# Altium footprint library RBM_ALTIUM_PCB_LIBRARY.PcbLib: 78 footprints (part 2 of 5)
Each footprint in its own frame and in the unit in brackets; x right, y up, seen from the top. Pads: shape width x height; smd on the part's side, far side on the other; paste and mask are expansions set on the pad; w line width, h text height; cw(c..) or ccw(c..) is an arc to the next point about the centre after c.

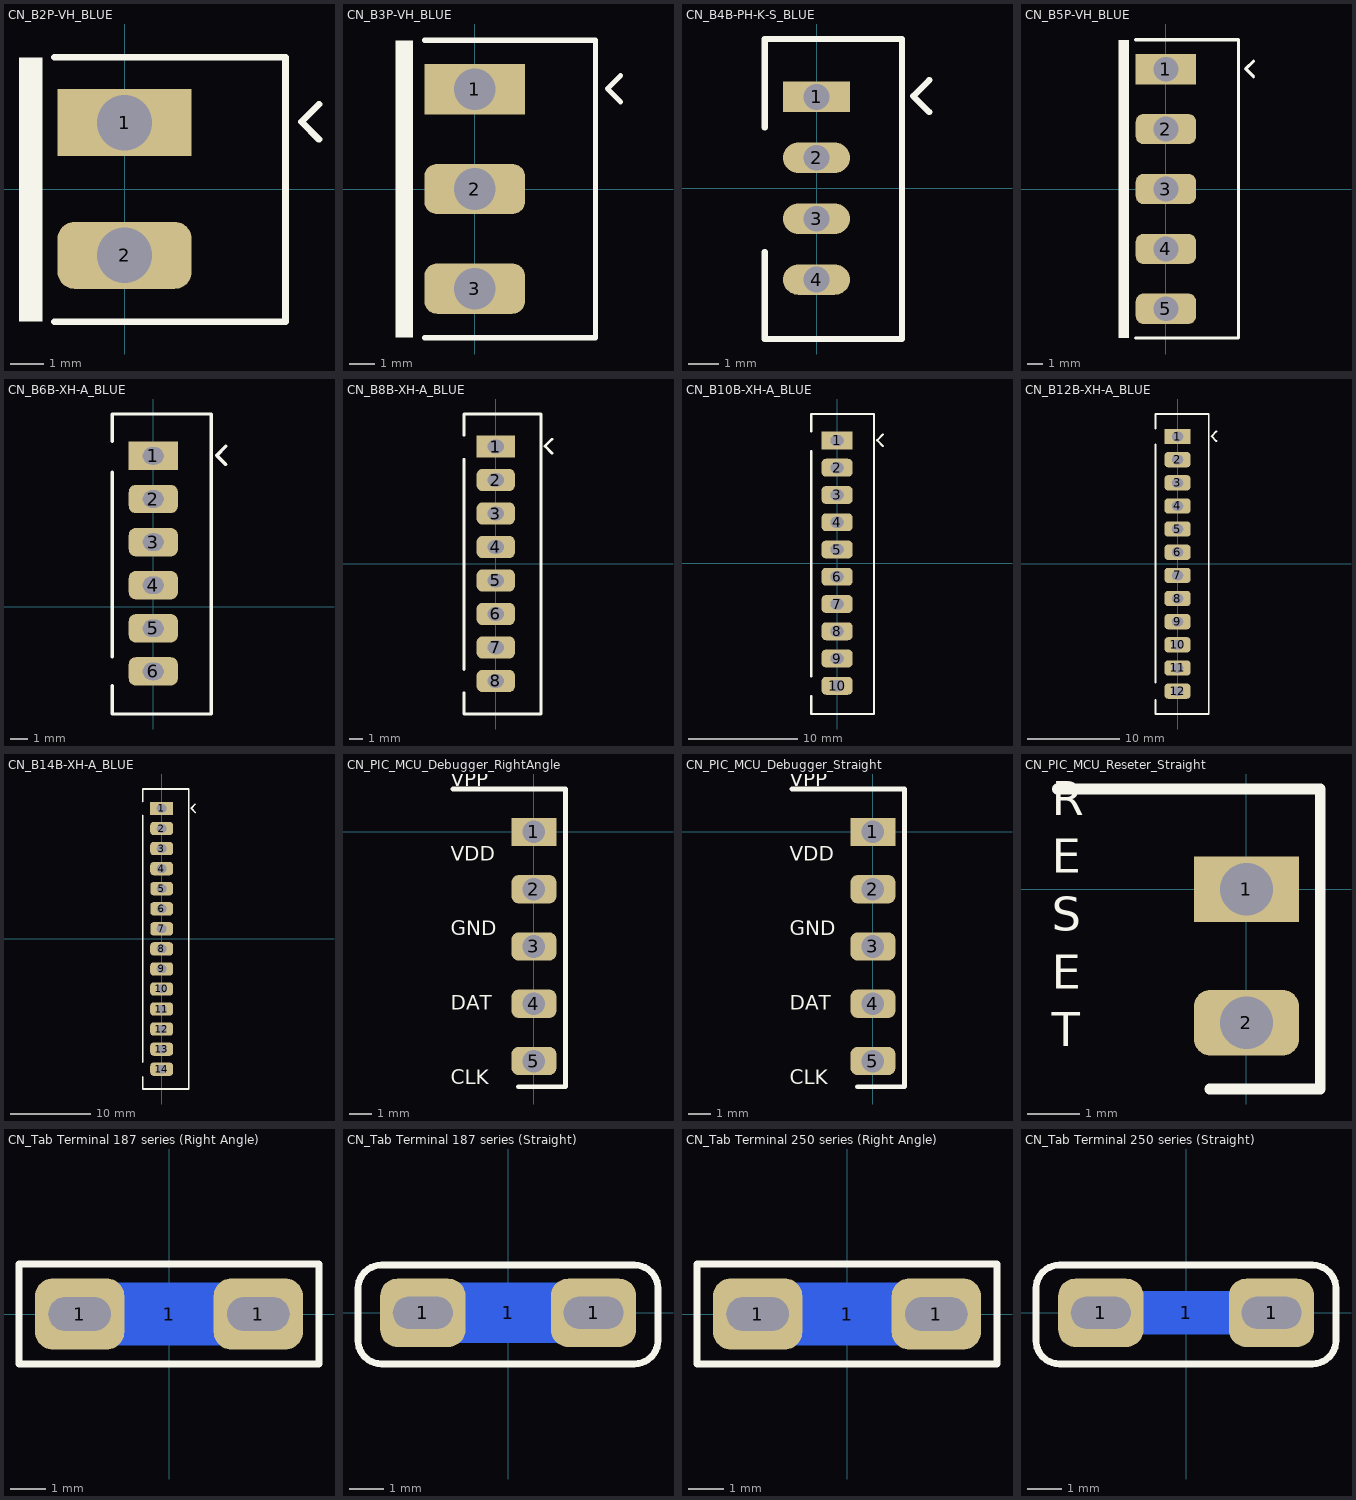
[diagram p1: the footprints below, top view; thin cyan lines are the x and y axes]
## CN_B2P-VH_BLUE [mm] "3.96mm Pitch"
pads (2):
  rect 4x2 hole 1.65: 1(0,1.98)
  rrect50% 4x2 hole 1.65: 2(0,-1.98)
Top Overlay:
  rectangle: -3.15,-3.96 -2.45,3.93
  lines w0.2: -2.1,-3.96 4.8,-3.96 4.8,3.93 -2.1,3.93 ; 5.8,1.48 5.275,2.005 5.8,2.53
3D body "B2P-VH.STEP": height 10.9, standoff -3.7, extent -3.75,-3.96 4.75,3.9

## CN_B3P-VH_BLUE [mm] "3.96mm Pitch"
pads (3):
  rect 4x2 hole 1.65: 1(0,3.96)
  rrect50% 4x2 hole 1.65: 2(0,0) 3(0,-3.96)
Top Overlay:
  rectangle: -3.15,-5.91 -2.45,5.91
  lines w0.2: -2,-5.91 4.8,-5.91 4.8,5.91 -2,5.91 ; 5.8,3.46 5.275,3.985 5.8,4.51
3D body "B3P-VH.STEP": height 10.9, standoff -3.7, extent -3.7,-5.91 4.8,5.91

## CN_B4B-PH-K-S_BLUE [mm] "Top Entry Header 2mm pitch 1X4pin  180° long"
pads (4):
  rect 2.2x1 hole 0.85: 1(0,3)
  oval 2.2x1 hole 0.85: 2(0,1) 3(0,-1) 4(0,-3)
Top Overlay:
  lines w0.2: -1.7,-2.1 -1.7,-4.95 2.8,-4.95 2.8,4.9 -1.7,4.9 -1.7,2 ; 3.7,2.5 3.175,3.025 3.7,3.55
3D body "B4B-PH-K-S.STEP": height 6, standoff -3.4, extent -1.7,-5 2.8,4.9

## CN_B5P-VH_BLUE [mm] "3.96mm Pitch"
pads (5):
  rect 4x2 hole 1.65: 1(0,7.92)
  rrect50% 4x2 hole 1.65: 2(0,3.96) 3(0,0) 4(0,-3.96) 5(0,-7.92)
Top Overlay:
  rectangle: -3.15,-9.85 -2.45,9.87
  lines w0.2: -2,-9.85 4.8,-9.85 4.8,9.87 -2,9.87 ; 5.8,7.42 5.275,7.945 5.8,8.47
3D body "B5P-VH.STEP": height 10.9, standoff -3.7, extent -3.65,-9.85 4.85,9.89

## CN_B6B-XH-A_BLUE [mm] "2.5mm Pitch, 8pins, Top-Entry, XH Connector"
pads (6):
  rect 2.85x1.65 hole 1.2 slot 1 at 90 deg: 1(0,8.75)
  rrect50% 2.85x1.65 hole 1.2 slot 1 at 90 deg: 2(0,6.25) 3(0,3.75) 4(0,1.25) 5(0,-1.25) 6(0,-3.75)
Top Overlay:
  lines w0.2: -2.375,-6.22 3.375,-6.22 3.375,11.18 -2.375,11.18 -2.375,9.6 ; -2.375,-6.15 -2.375,-4.57 ; -2.375,-2.9 -2.375,7.8 ; 4.2,8.25 3.675,8.775 4.2,9.3
3D body "B6B-XH-A.STEP": height 7, standoff -3.4, extent -2.375,-6.22 3.375,11.18

## CN_B8B-XH-A_BLUE [mm] "2.5mm Pitch, 8pins, Top-Entry, XH Connector"
pads (8):
  rect 2.85x1.65 hole 1.2 slot 1 at 90 deg: 1(0,8.75)
  rrect50% 2.85x1.65 hole 1.2 slot 1 at 90 deg: 2(0,6.25) 3(0,3.75) 4(0,1.25) 5(0,-1.25) 6(0,-3.75) 7(0,-6.25) 8(0,-8.75)
Top Overlay:
  lines w0.2: -2.375,-9.64 -2.375,-11.22 3.375,-11.22 3.375,11.18 -2.375,11.18 -2.375,9.6 ; -2.375,-7.9 -2.375,7.8 ; 4.2,8.25 3.675,8.775 4.2,9.3
3D body "B8B-XH-A.STEP": height 7, standoff -3.4, extent -2.375,-11.22 3.375,11.18

## CN_B10B-XH-A_BLUE [mm] "2.5mmPitch, TopEntry, BlueColor, XH Connector"
pads (10):
  rect 2.85x1.65 hole 1.2 slot 1 at 90 deg: 1(0,11.25)
  rrect50% 2.85x1.65 hole 1.2 slot 1 at 90 deg: 2(0,8.75) 3(0,6.25) 4(0,3.75) 5(0,1.25) 6(0,-1.25) 7(0,-3.75) 8(0,-6.25) 9(0,-8.75) 10(0,-11.25)
Top Overlay:
  lines w0.2: -2.375,-12.2 -2.375,-13.84 3.375,-13.84 3.375,13.68 -2.375,13.68 -2.375,12.1 ; -2.375,-10.4 -2.375,10.3 ; 4.2,10.75 3.675,11.275 4.2,11.8
3D body "B10B-XH-A.STEP": height 7, standoff -3.4, extent -2.375,-13.72 3.375,13.68

## CN_B12B-XH-A_BLUE [mm] "2.5mmPitch, TopEntry, BlueColor, XH Connector"
pads (12):
  rect 2.85x1.65 hole 1.2 slot 1 at 90 deg: 1(0,13.75)
  rrect50% 2.85x1.65 hole 1.2 slot 1 at 90 deg: 2(0,11.25) 3(0,8.75) 4(0,6.25) 5(0,3.75) 6(0,1.25) 7(0,-1.25) 8(0,-3.75) 9(0,-6.25) 10(0,-8.75) 11(0,-11.25) 12(0,-13.75)
Top Overlay:
  lines w0.2: -2.375,-14.7 -2.375,-16.22 3.375,-16.22 3.375,16.18 -2.375,16.18 -2.375,14.6 ; -2.375,-12.8 -2.375,12.9 ; 4.2,13.25 3.675,13.775 4.2,14.3
3D body "B12B-XH-A.STEP": height 7, standoff -3.4, extent -2.375,-16.22 3.375,16.18

## CN_B14B-XH-A_BLUE [mm] "2.5mmPitch, TopEntry, BlueColor, XH Connector"
pads (14):
  rect 2.85x1.65 hole 1.2 slot 1 at 90 deg: 1(0,16.25)
  rrect50% 2.85x1.65 hole 1.2 slot 1 at 90 deg: 2(0,13.75) 3(0,11.25) 4(0,8.75) 5(0,6.25) 6(0,3.75) 7(0,1.25) 8(0,-1.25) 9(0,-3.75) 10(0,-6.25) 11(0,-8.75) 12(0,-11.25) 13(0,-13.75) 14(0,-16.25)
Top Overlay:
  lines w0.2: -2.375,-17.2 -2.375,-18.72 3.375,-18.72 3.375,18.68 -2.375,18.68 -2.375,17.1 ; -2.375,-15.4 -2.375,15.4 ; 4.2,15.75 3.675,16.275 4.2,16.8
3D body "B14B-XH-A.STEP": height 7, standoff -3.4, extent -2.375,-18.72 3.375,18.68

## CN_PIC_MCU_Debugger_RightAngle [mm] "2.54mmPitch, 5pins, StraightType, Male Connector"
pads (5):
  rect 2x1.25 hole 1: 1(0,0)
  rrect50% 2x1.25 hole 1: 2(0,-2.54) 3(0,-5.08) 4(0,-7.62) 5(0,-10.16)
Top Overlay:
  lines w0.203: -3.6,1.905 1.4,1.905 1.4,-11.3 -0.7,-11.3
  text "VPP /  /  / VDD /  /  / GND /  /  / DAT /  /  / CLK" at -3.7,-11.4 h1.1
Bottom Overlay:
  lines w0.203: -3.6,1.9 1.4,1.9 1.4,-11.305 -0.7,-11.305
  text "VPP /  /  / VDD /  /  / GND /  /  / DAT /  /  / CLK" at -1.3,-11.4 h1.1
3D body "5-Way 2.54mm Right Angle Male Header.STEP": height 2.51, standoff -3, extent -0.365,-11.4 9.765,1.3

## CN_PIC_MCU_Debugger_Straight [mm] "2.54mmPitch, 5pins, StraightType, Male Connector"
pads (5):
  rect 2x1.25 hole 1: 1(0,0)
  rrect50% 2x1.25 hole 1: 2(0,-2.54) 3(0,-5.08) 4(0,-7.62) 5(0,-10.16)
Top Overlay:
  lines w0.203: -3.6,1.905 1.4,1.905 1.4,-11.3 -0.7,-11.3
  text "VPP /  /  / VDD /  /  / GND /  /  / DAT /  /  / CLK" at -3.7,-11.4 h1.1
Bottom Overlay:
  lines w0.203: -3.6,1.9 1.4,1.9 1.4,-11.305 -0.7,-11.305
  text "VPP /  /  / VDD /  /  / GND /  /  / DAT /  /  / CLK" at -1.3,-11.4 h1.1
3D body "5Pins 2.54mm Male Header.STEP": height 8.54, standoff -3, extent -1.245,-11.43 1.245,1.27

## CN_PIC_MCU_Reseter_Straight [mm] "2.54mmPitch, 2pins, StraightType, Male Connector"
pads (2):
  rect 2x1.25 hole 1: 1(0,0)
  rrect50% 2x1.25 hole 1: 2(0,-2.54)
Top Overlay:
  lines w0.203: -3.6,1.905 1.4,1.905 1.4,-3.8 -0.7,-3.8
  text "R / E / S / E / T" at -3.7,-3.2 h1.1
Bottom Overlay:
  lines w0.203: -3.6,1.9 1.4,1.9 1.4,-3.8 -0.7,-3.8
  text "R / E / S / E / T" at -1.3,-3.2 h1.1
3D body "User Library-Header_Male_2Pin.STEP": height 8.54, standoff -3, extent -1.245,-3.81 1.245,1.27

## CN_Tab Terminal 187 series (Right Angle) [mm]
pads (3):
  rrect50% 2.5x2 hole 0.95 slot 1.75 at 0 deg: 1(-2.5,0) 1(2.5,0)
  rect 2.85x1.75 smd far side: 1(0,0)
Top Overlay:
  lines w0.2: -4.2,-1.397 -4.2,1.397 4.2,1.397 4.2,-1.397 -4.2,-1.397
3D body "4.8mm PCB Tab Terminal (Right Angle).stp": height 9.3, standoff -3.7, extent -3.3,-0.4 9.5,0.4

## CN_Tab Terminal 187 series (Straight) [mm]
pads (3):
  rrect50% 2.5x2 hole 0.95 slot 1.75 at 0 deg: 1(-2.5,0) 1(2.5,0)
  rect 2.85x1.75 smd far side: 1(0,0)
Top Overlay:
  lines w0.2: -4.4,-0.81 ccw(c-3.712,-0.81) -3.712,-1.498 3.7,-1.497 ccw(c3.7,-0.81) 4.388,-0.81 ; -4.4,-0.8 -4.4,0.712 ; -4.4,0.71 cw(c-3.712,0.71) -3.712,1.398 ; -3.712,1.397 3.7,1.397 ; 3.7,1.398 cw(c3.7,0.71) 4.388,0.71 ; 4.388,-0.812 4.388,0.7
3D body "4.8mm PCB Tab Terminal (Straight).stp": height 9, standoff -3.45, extent -3.962,-1.3 3.962,1.494

## CN_Tab Terminal 250 series (Right Angle) [mm]
pads (3):
  rrect50% 2.5x2 hole 0.95 slot 1.75 at 0 deg: 1(-2.5,0) 1(2.5,0)
  rect 2.85x1.75 smd far side: 1(0,0)
Top Overlay:
  lines w0.2: -4.2,-1.397 4.2,-1.397 4.2,1.397 -4.2,1.397 -4.2,-1.397
3D body "6.3mm PCB Tab Terminal (Right Angle).STEP": height 9.1, standoff -2.9, extent -4,-0.4 12.2,0.4

## CN_Tab Terminal 250 series (Straight) [mm]
pads (3):
  rrect50% 2.5x2 hole 0.95 slot 1.75 at 0 deg: 1(-2.5,0) 1(2.5,0)
  rect 2.85x1.25 smd far side: 1(0,0)
Top Overlay:
  lines w0.2: -4.4,-0.81 ccw(c-3.712,-0.81) -3.712,-1.498 3.7,-1.497 ccw(c3.7,-0.81) 4.388,-0.81 ; -4.4,-0.8 -4.4,0.712 ; -4.4,0.71 cw(c-3.712,0.71) -3.712,1.398 ; -3.712,1.397 3.7,1.397 ; 3.7,1.398 cw(c3.7,0.71) 4.388,0.71 ; 4.388,-0.812 4.388,0.7
3D body "6.3mm PCB Tab Terminal (Straight).stp": height 10.2, standoff -3.8, extent -4,-0.4 4,0.4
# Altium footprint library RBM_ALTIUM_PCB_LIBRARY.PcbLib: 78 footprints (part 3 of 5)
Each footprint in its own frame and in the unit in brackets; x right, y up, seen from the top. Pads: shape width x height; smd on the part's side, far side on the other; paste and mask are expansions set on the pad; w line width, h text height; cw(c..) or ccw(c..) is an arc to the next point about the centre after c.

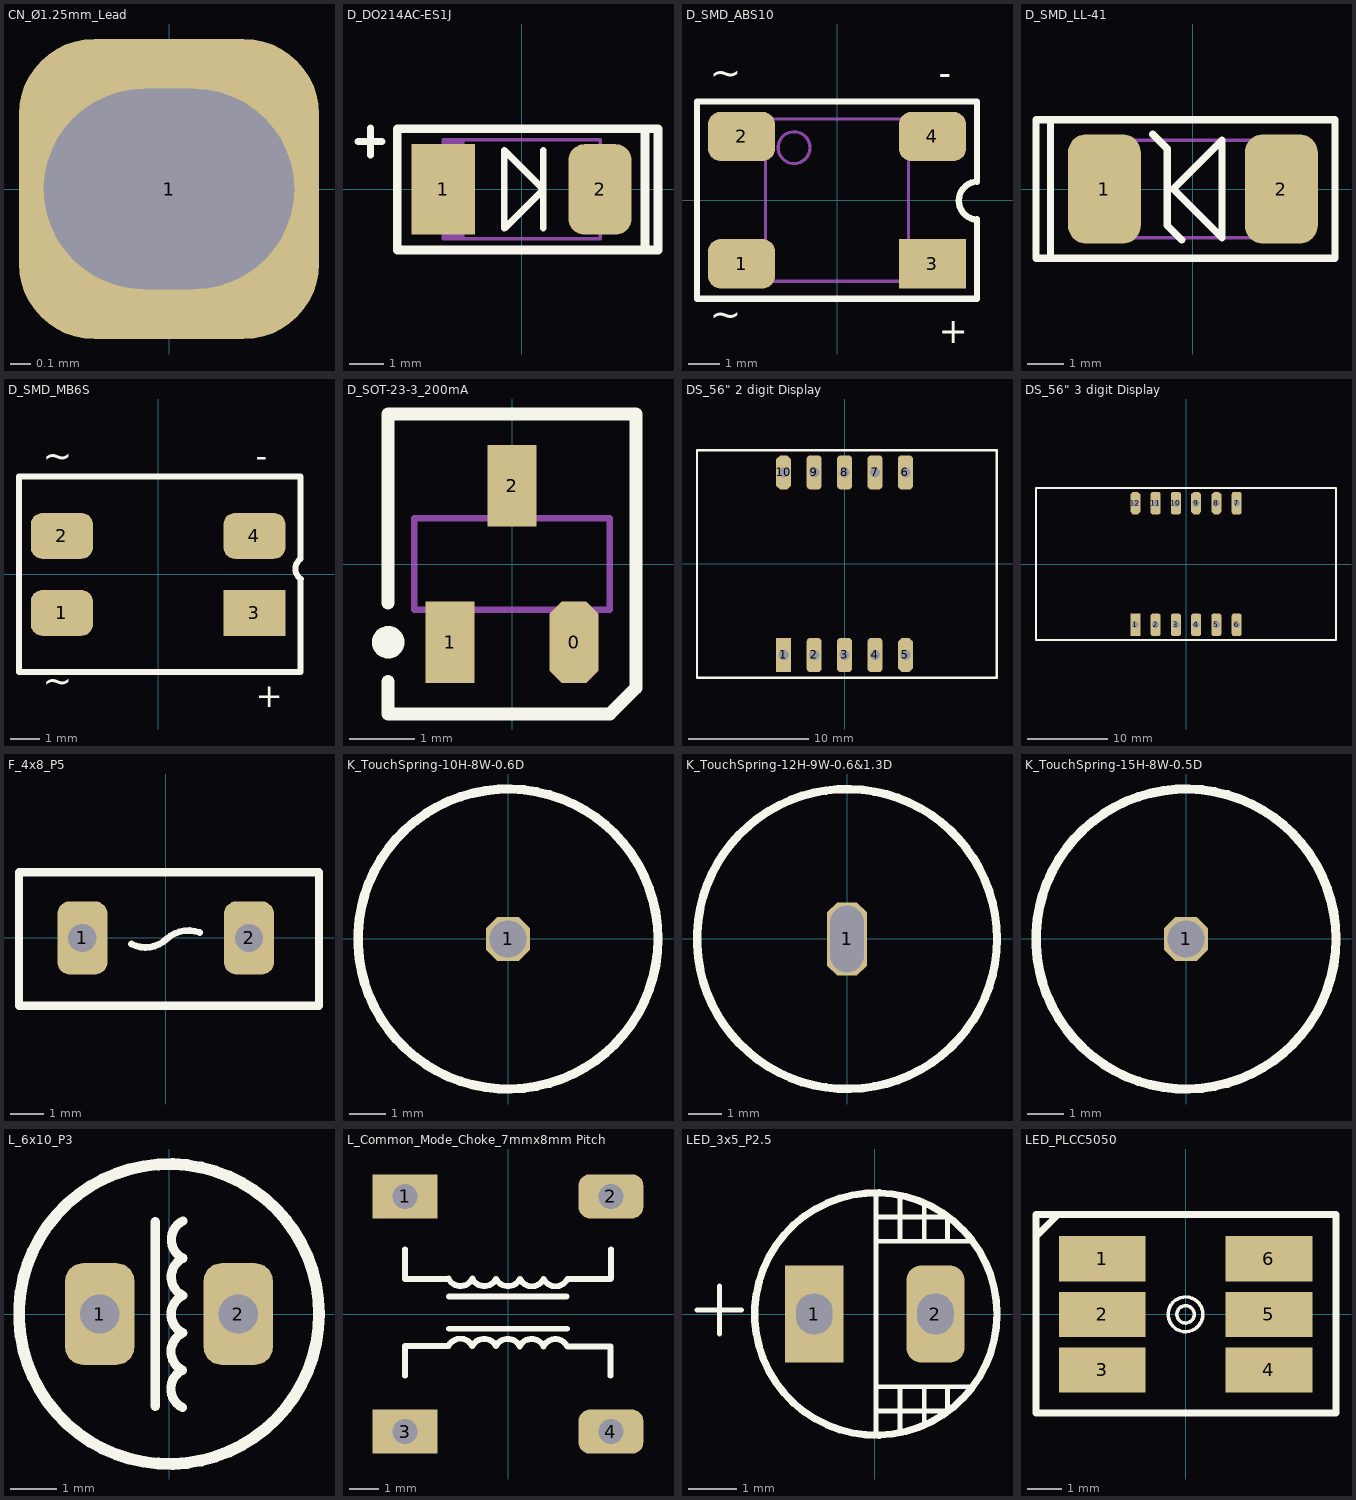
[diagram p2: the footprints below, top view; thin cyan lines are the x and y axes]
## CN_Ø1.25mm_Lead [mm] "Lead Wire"
pads (1):
  rrect50% 1.5x1.5 / inner rrect50% 1.5x1.5 / far side rrect50% 2.5x1.5 hole 1.25 slot 1 at 90 deg: 1(0,0)

## D_DO214AC-ES1J [mm] "Molded Diode, 2-Leads, Body 4.29x2.69mm, IPC Medium Density"
height 2.44
pads (2):
  rect 1.85x2.65 smd: 1(-2.3,0)
  rrect50% 1.85x2.65 smd: 2(2.3,0)
Top Overlay:
  lines w0.2: -4.8,1.4 -4.1,1.4 ; -4.435,1 -4.435,1.8 ; 0.635,-1.143 0.635,1.143 ; -0.508,-1.143 0.635,0 -0.508,1.143 -0.508,-1.143
  lines w0.254: 3.619,-1.778 3.619,1.778 ; -3.65,-1.778 4,-1.778 4,1.778 -3.65,1.778 -3.65,-1.778
Mechanical 13:
  rectangle: -2.3,-1.45 -1.681,1.45
  lines w0.1: -2.3,-1.45 2.3,-1.45 2.3,1.45 -2.3,1.45 -2.3,-1.45
3D body "DIOM4327X24N.step": height 2.44, standoff 0, extent -2.52,-1.45 2.52,1.45

## D_SMD_ABS10 [mm]
pads (4):
  rrect50% 2.1x1.55 smd: 1(-3,-2) 2(-3,2) 4(3,2)
  rect 2.1x1.55 smd: 3(3,-2)
Top Overlay:
  lines w0.2: 4.299,-0.603 cw(c4.427,-0.017) 4.306,0.57 ; 4.4,-0.603 4.4,-3.1 -4.4,-3.1 -4.4,3.1 4.4,3.1 4.4,0.57
  text "~" at -4,-4.3 h1.5
  text "-" at 3.2,4.2 h0.8
  text "+" at 3.2,-3.8 h0.8
  text "~" at -4,3.3 h1.5
Mechanical 13:
  circle w0.1: c-1.35,1.65 r0.5
  lines w0.1: -2.25,-2.55 -2.25,2.55 2.25,2.55 2.25,-2.55 -2.25,-2.55
3D body "TSOP400P650X160-4N.step": height 1.6, standoff 0, extent -3.25,-2.55 3.25,2.55

## D_SMD_LL-41 [mm]
height 2.67
pads (2):
  rrect50% 2x3 smd: 1(-2.425,0) 2(2.425,0)
Top Overlay:
  lines w0.2: -3.9,-1.8 -3.9,1.8 ; -1.1,1.5 -0.7,1.1 -0.7,-1 -0.3,-1.4 ; -4.3,-1.9 3.9,-1.9 3.9,1.9 -4.3,1.9 -4.3,-1.9 ; -0.535,0 0.8,1.335 0.8,-1.335 -0.535,0
Mechanical 13:
  lines w0.1: -2.75,-1.335 -2.75,1.335 2.75,1.335 2.75,-1.335 -2.75,-1.335
3D body "ZD.step": height 2.46, standoff 0.01, extent -2.575,-1.227 2.575,1.228

## D_SMD_MB6S [mm]
pads (4):
  rrect50% 2.1x1.55 smd: 1(-3.25,-1.3) 2(-3.25,1.3) 4(3.25,1.3)
  rect 2.1x1.55 smd: 3(3.25,-1.3)
Top Overlay:
  lines w0.2: 4.8,-0.153 4.8,-3.3 -4.7,-3.3 -4.7,3.3 4.8,3.3 4.8,0.523 ; 4.813,0.523 ccw(c5.028,0.186) 4.816,-0.153
  text "~" at -3.9,-4.3 h1.5
  text "-" at 3.3,4.2 h0.8
  text "+" at 3.3,-3.8 h0.8
  text "~" at -3.9,3.3 h1.5
3D body "User Library-moste3k.STEP": height 1.45, standoff -0.08, extent -3.447,-2.417 3.453,2.577

## D_SOT-23-3_200mA [mm] "Diodes - General Purpose 100V 200mA 1.25V @ 200mA SOT-23(SOT-23-3) RoHS"
height 1.15
pads (3):
  oct 0.75x1.25 smd: 0(0.95,-1.2)
  rect 0.75x1.25 smd: 1(-0.95,-1.2) 2(0,1.2)
Top Overlay:
  circle w0.25: c-1.9,-1.2 r0.125
  lines w0.2: -1.9,-1.8 -1.9,-2.3 1.5,-2.3 1.9,-1.9 1.9,2.3 -1.9,2.3 -1.9,-0.6
Mechanical 13:
  lines w0.1: -1.5,-0.7 1.5,-0.7 1.5,0.7 -1.5,0.7 -1.5,-0.7
3D body "SOT95P245X115-3N.step": height 1.15, standoff 0, extent -1.5,-1.3 1.5,1.3

## DS_56" 2 digit Display [mm]
pads (10):
  rect 1.25x2.85 hole 0.85: 1(-5.08,-7.62)
  rrect50% 1.25x2.85 hole 0.85: 2(-2.54,-7.62) 3(0,-7.62) 4(2.54,-7.62) 6(5.08,7.62) 7(2.54,7.62) 8(0,7.62) 9(-2.54,7.62)
  oct 1.25x2.85 hole 0.85: 5(5.08,-7.62) 10(-5.08,7.62)
Top Overlay:
  lines w0.2: -12.319,-9.525 -12.319,9.475 12.7,9.475 12.7,-9.525 ; -12.28,-9.525 12.72,-9.525
Bottom Overlay:
  text "D2" at 5.8,-5 h1
  text "D1" at -4.4,4.1 h1
  text "a" at 2.9,4.167 h1
  text "b" at 5.38,4.167 h1
  text "f" at 0.301,4.167 h1
  text "g" at -2.24,4.3 h1
  text "c" at 2.742,-4.833 h1
  text "e" at 0.201,-4.833 h1
  text "dp" at -1.738,-4.9 h1
  text "d" at -4.878,-4.833 h1
3D body: height 3, standoff -3, extent -5.338,7.361 -4.82,7.88
3D body: height 3, standoff -3, extent -2.798,7.361 -2.28,7.88
3D body: height 3, standoff -3, extent -0.258,7.361 0.26,7.88
3D body: height 3, standoff -3, extent 2.282,7.361 2.8,7.88
3D body: height 3, standoff -3, extent 4.822,7.361 5.34,7.88
3D body: height 3, standoff -3, extent -5.338,-7.879 -4.82,-7.36
3D body: height 3, standoff -3, extent 4.822,-7.879 5.34,-7.36
3D body: height 3, standoff -3, extent 2.282,-7.879 2.8,-7.36
3D body: height 3, standoff -3, extent -0.258,-7.879 0.26,-7.36
3D body: height 3, standoff -3, extent -2.798,-7.879 -2.28,-7.36
3D body: height 7, standoff 1, extent -12.319,-9.525 12.7,9.398
3D body: height 7, standoff 1, extent -12.3,-9.313 12.719,9.61
3D body: height 8.1, standoff -5.5, extent -16.11,10.118 -16.11,10.118

## DS_56" 3 digit Display [mm]
pads (12):
  rect 1.25x2.85 hole 0.85: 1(-6.35,-7.62)
  rrect50% 1.25x2.85 hole 0.85: 2(-3.81,-7.62) 3(-1.27,-7.62) 4(1.27,-7.62) 5(3.81,-7.62) 6(6.35,-7.62) 7(6.35,7.62) 10(-1.27,7.62) 11(-3.81,7.62)
  oct 1.25x2.85 hole 0.85: 8(3.81,7.62) 9(1.27,7.62) 12(-6.35,7.62)
Top Overlay:
  lines w0.2: -18.796,-9.525 -18.796,9.525 18.796,9.525 18.796,-9.525 -18.796,-9.525
Bottom Overlay:
  text "D1" at -5.67,4.2 h1
  text "D2" at 2.13,4.2 h1
  text "D3" at 4.64,4.2 h1
  text "d" at -3.5,-4.8 h1
  text "dp" at -0.5,-4.7 h1
  text "e" at -6.1,-4.767 h1
  text "c" at 1.6,-4.7 h1
  text "g" at 4.1,-4.567 h1
  text "f" at -1.07,4.3 h1
  text "b" at 6.73,4.2 h1
  text "a" at -3.37,4.3 h1
3D body "User Library-5631_w_o_color_jam.step": height 8.1, standoff -5.5, extent -18.796,-9.525 18.804,9.475

## F_4x8_P5 [mm]
pads (2):
  rrect50% 1.5x2.2 hole 0.85: 1(-2.5,0) 2(2.5,0)
Top Overlay:
  lines w0.2: -1.028,-0.184 ccw(c-0.609,0.633) 0.034,-0.022 ; 0.001,-0.057 cw(c0.685,-0.753) 1.023,0.162
  lines w0.254: -4.402,-2.032 4.598,-2.032 4.598,1.968 -4.402,1.968 -4.402,-2.032
3D body: height 7, standoff 0.68, extent -4.505,-1.968 4.512,1.968
3D body: height 1.5, standoff -2, extent -2.797,-0.299 -2.199,0.3
3D body: height 1.5, standoff -2, extent 2.203,-0.299 2.801,0.3

## K_TouchSpring-10H-8W-0.6D [mm]
pads (1):
  oct 1.2x1.2 / inner oct 1x1 / far side oct 2.5x2.5 hole 1: 1(0,0)
Top Overlay:
  circle w0.254: c0,0 r4.09
3D body: height 3, standoff -3, extent 0,0 0,0
3D body: height 10, standoff 0, extent -4,-3.997 4,3.997
3D body: height 3, standoff -3, extent -0.258,-0.259 0.26,0.26

## K_TouchSpring-12H-9W-0.6&1.3D [mm]
pads (1):
  oct 1.2x2.2 / inner oct 1x1 / far side oct 3x3 hole 2 slot 1 at 0 deg: 1(0,0)
Top Overlay:
  circle w0.254: c0,0 r4.5
3D body: height 12, standoff 0, extent -4.5,-4.5 4.5,4.5
3D body: height 3, standoff -3, extent 0,0 0,0
3D body: height 5, standoff -3, extent -0.3,-0.7 0.3,0.7

## K_TouchSpring-15H-8W-0.5D [mm]
pads (1):
  oct 1.2x1.2 / inner oct 1x1 / far side oct 2.5x2.5 hole 1: 1(0,0)
Top Overlay:
  circle w0.254: c0,0 r4.09
3D body: height 3, standoff -3, extent -0.258,-0.259 0.26,0.26
3D body: height 15, standoff 0, extent -4,-3.997 4,3.997
3D body: height 3, standoff -3, extent 0,0 0,0

## L_6x10_P3 [mm]
pads (2):
  rrect50% 1.5x2.2 hole 0.85: 1(-1.5,0) 2(1.5,0)
Top Overlay:
  circle w0.254: c0,0 r3.25
  lines w0.2: -0.3,-2 -0.3,2 ; 0.293,-2.025 cw(c0.489,-1.622) 0.295,-1.217 cw(c0.492,-0.813) 0.298,-0.408 cw(c0.494,-0.005) 0.3,0.4 cw(c0.497,0.804) 0.302,1.208 cw(c0.499,1.612) 0.305,2.017
3D body: height 2, standoff -1, extent 1.202,-0.299 1.8,0.3
3D body: height 2, standoff -1, extent -1.799,-0.299 -1.201,0.299
3D body: height 13, standoff 10, extent -3.242,-3.316 3.258,3.177
3D body: height 3.25, standoff 0.25, extent -3.242,-3.316 3.258,3.177
3D body: height 11.5, standoff 0.5, extent -2.993,-3.07 3.006,2.93

## L_Common_Mode_Choke_7mmx8mm Pitch [mm] "1~22mH, 1000~200mA"
pads (4):
  rect 2.2x1.5 hole 0.85: 1(-3.5,4) 3(-3.5,-4)
  rrect50% 2.2x1.5 hole 0.85: 2(3.5,4) 4(3.5,-4)
Top Overlay:
  lines w0.2: -3.5,-2.1 -3.5,-1.093 -2.025,-1.093 cw(c-1.622,-1.289) -1.217,-1.095 cw(c-0.813,-1.292) -0.408,-1.098 cw(c-0.005,-1.294) 0.4,-1.1 cw(c0.804,-1.297) 1.208,-1.102 cw(c1.612,-1.299) 2.017,-1.105 3.488,-1.105 3.488,-2.1 ; -3.5,2.2 -3.5,1.193 -2.034,1.193 -2.022,1.205 ccw(c-1.617,1.399) -1.213,1.202 ccw(c-0.808,1.397) -0.405,1.2 ccw(c0,1.394) 0.404,1.198 ccw(c0.808,1.392) 1.212,1.195 ccw(c1.617,1.389) 2.02,1.193 3.488,1.193 3.5,1.205 3.5,2.2 ; -2.005,0.6 1.995,0.6 ; -2,-0.5 2,-0.5

## LED_3x5_P2.5 [mm]
pads (2):
  rect 1.2x2 hole 0.85 slot 0.75 at 0 deg: 1(-1.25,0)
  rrect50% 1.2x2 hole 0.85 slot 0.75 at 0 deg: 2(1.25,0)
Top Overlay:
  circle w0.15: c0.02,0 r2.5
  lines w0.1: -3.67,0.083 -2.754,0.083 ; -3.203,-0.417 -3.203,0.583 ; 0.02,-2.5 0.02,2.5 ; 0.02,-2 1.5,-2 1.5,-1.5 ; 0.02,-1.5 2.014,-1.5 ; 0.02,1.5 2.014,1.5 ; 0.02,2 1.5,2 1.5,1.5 ; 0.52,-2.4 0.52,-1.5 ; 0.52,1.5 0.52,2.4 ; 1.02,-2.3 1.02,-1.5 ; 1.02,1.5 1.02,2.3
3D body "LED_3x5_P2.5.STEP": height 7.38, standoff -1.17, extent -1.974,-1.498 2.014,1.994

## LED_PLCC5050 [mm] "EDISON RGB .2W"
pads (6):
  rect 2.5x1.3 smd: 1(-2.4,1.6) 2(-2.4,0) 3(-2.4,-1.6) 4(2.4,-1.6) 5(2.4,0) 6(2.4,1.6)
Top Overlay:
  circle w0.1: c0,0 r0.5
  circle w0.1: c0,0 r0.25
  lines w0.2: -4.305,2.235 -3.67,2.87 ; -4.305,-2.845 4.331,-2.845 4.331,2.87 -4.305,2.87 -4.305,-2.845
3D body "User Library-APA102C.step": height 1.51, standoff -0.04, extent -2.75,-2.5 2.75,2.5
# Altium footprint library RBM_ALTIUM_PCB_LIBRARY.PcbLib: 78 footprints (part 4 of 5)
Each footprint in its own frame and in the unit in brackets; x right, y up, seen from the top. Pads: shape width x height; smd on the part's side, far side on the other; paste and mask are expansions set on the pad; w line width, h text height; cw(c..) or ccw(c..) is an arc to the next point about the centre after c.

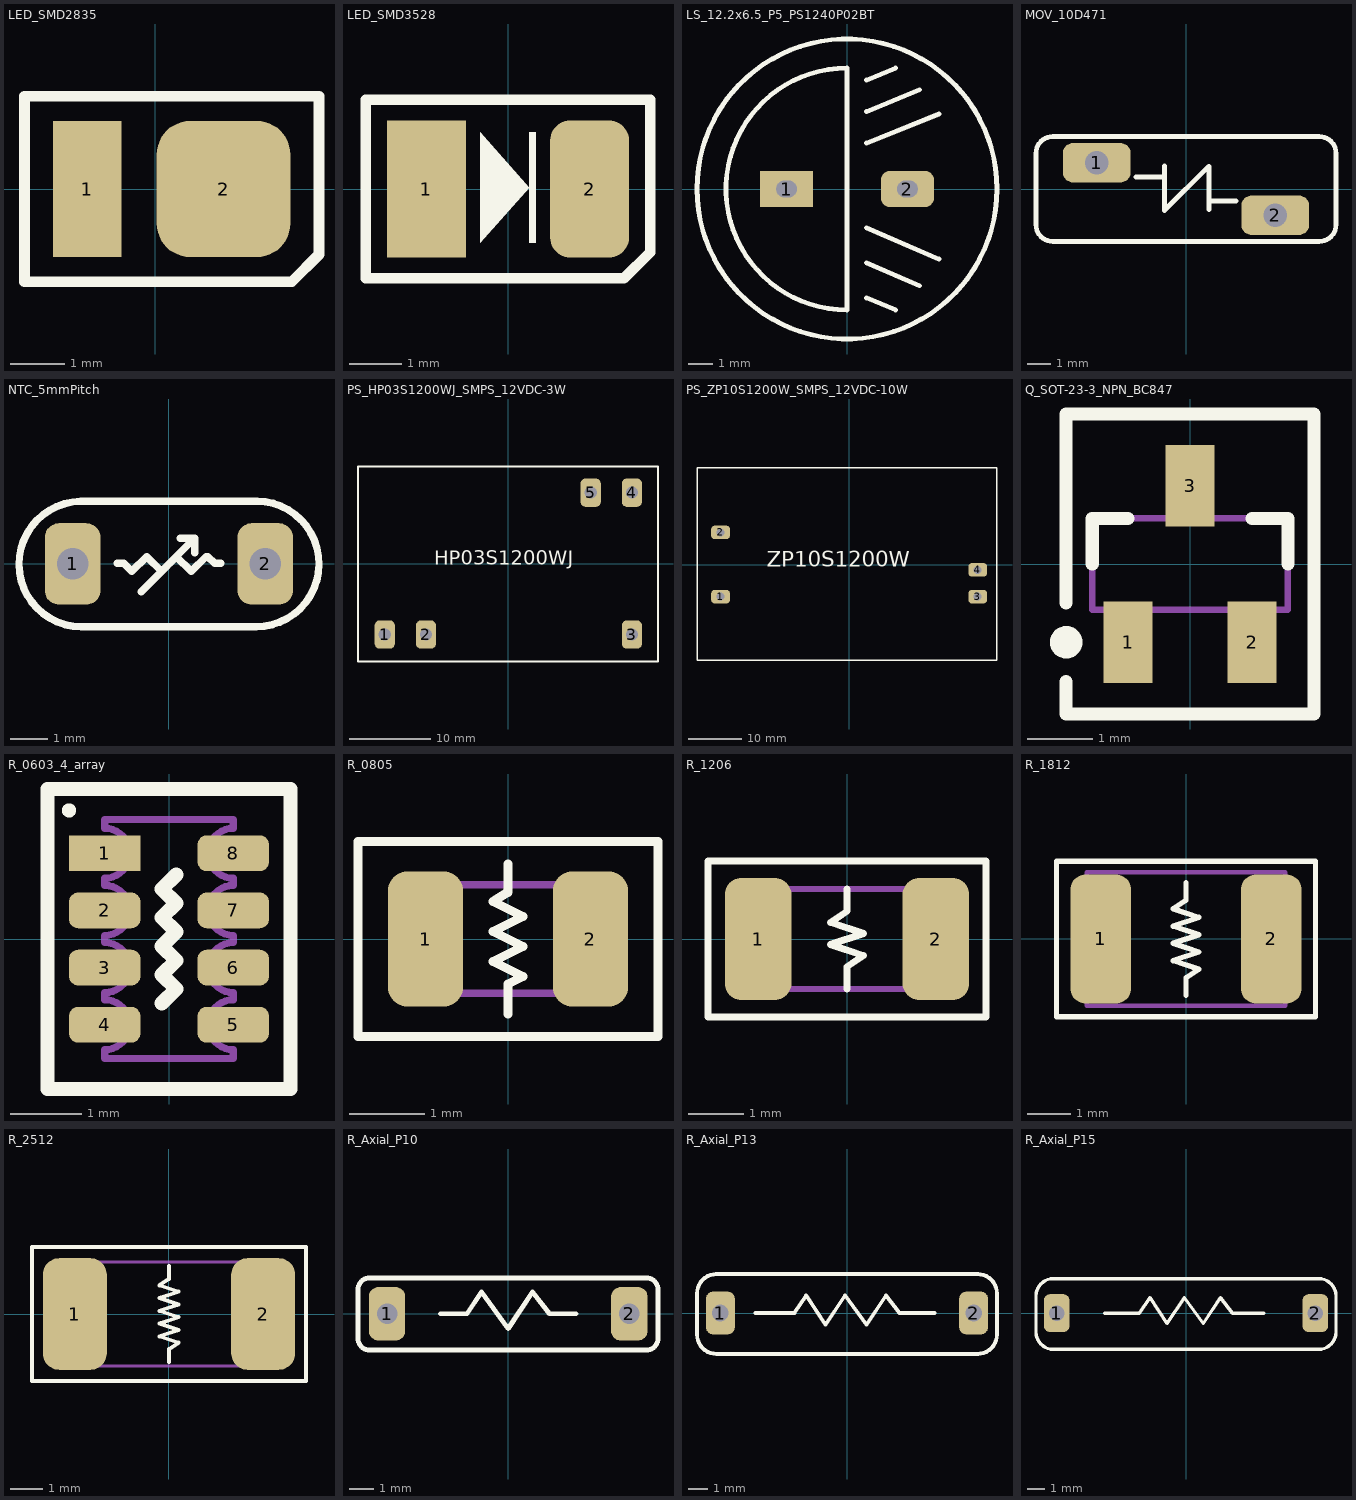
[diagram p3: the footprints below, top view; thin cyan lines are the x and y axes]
## LED_SMD2835 [mm]
pads (2):
  rect 1.25x2.5 smd: 1(-1.25,0)
  rrect50% 2.45x2.5 smd: 2(1.25,0)
Top Overlay:
  region: 2.8,1.6
  lines w0.2: -2.4,-1.7 2.5,-1.7 3,-1.2 3,1.7 -2.4,1.7 -2.4,-1.7
3D body "LED_SMD-2835.STEP": height 0.7, standoff -0.02, extent -1.547,-1.4 2.017,1.4

## LED_SMD3528 [mm]
pads (2):
  rect 1.5x2.6 smd: 1(-1.55,0)
  rrect50% 1.5x2.6 smd: 2(1.55,0)
Top Overlay:
  region: 2.5,1.6
  region: -0.525,-1.025 -0.525,1.075 0.4,0.025
  region: 0.525,1.075 0.4,1.075 0.4,-1.025 0.525,-1.025
  lines w0.2: -2.7,-1.7 2.2,-1.7 2.7,-1.2 2.7,1.7 -2.7,1.7 -2.7,-1.7
3D body "LED_Osram_Led_PLCC4-2.step": height 1.95, standoff 0, extent -1.8,-1.4 1.7,1.4

## LS_12.2x6.5_P5_PS1240P02BT [mm] "PS1240P02BT, ø12.2x6.5 P5 70dB 4kHz 3~30V"
pads (2):
  rect 2.2x1.5 hole 0.7 slot 0.85 at 0 deg: 1(-2.5,0)
  rrect50% 2.2x1.5 hole 0.7 slot 0.85 at 0 deg: 2(2.5,0)
Top Overlay:
  circle w0.2: c0,0 r6.2
  lines w0.2: 0.8,-4.5 2,-5 ; 0.8,-3.046 3,-4 ; 0.8,-1.6 3.8,-2.9 ; 0.8,1.9 3.8,3.1 ; 0.8,3.2 3,4.1 ; 0.8,4.5 2,5 ; 0,-5 cw(c0,0) 0,5 0,-5
3D body: height 6.75, standoff 0.25, extent -6.1,-6.097 6.1,6.097
3D body: height 1, standoff -1, extent -2.829,-0.329 -2.171,0.329
3D body: height 1, standoff -1, extent 2.173,-0.329 2.83,0.33
3D body: height 6.8, standoff 0.3, extent -1.494,-1.497 1.494,1.497

## MOV_10D471 [mm]
pads (2):
  rrect50% 2.85x1.65 hole 1: 1(-3.75,1.1) 2(3.75,-1.1)
Top Overlay:
  lines w0.1: 0.998,-0.51 1.009,-0.5
  lines w0.2: -5.1,2.2 5.6,2.2 cw(c5.6,1.5) 6.3,1.5 6.3,-1.5 cw(c5.6,-1.5) 5.6,-2.2 -5.6,-2.2 cw(c-5.6,-1.5) -6.3,-1.5 -6.3,1.5 cw(c-5.6,1.5) -5.6,2.2 -4.9,2.2 ; -2.1,0.499 -0.921,0.499 ; -0.908,0.967 -0.908,-0.903 0.954,0.959 ; 0.967,-0.875 0.967,0.959 ; 1.009,-0.5 2.1,-0.5
3D body "User Library-S10K275.STEP": height 13.55, standoff -1.95, extent -6,-1.9 6,1.901
3D body: height 3, standoff -2, extent -4.158,0.691 -3.342,1.509
3D body: height 3, standoff -2, extent 3.343,-1.509 4.16,-0.691

## NTC_5mmPitch [mm]
pads (2):
  rrect50% 1.5x2.2 hole 0.85: 1(-2.6,0) 2(2.6,0)
Top Overlay:
  lines w0.1: -1.229,0.018 -1.218,0.018 ; 1,0.2 1.049,0.2 ; -0.6,0.2 -0.6,0.2 ; 0.6,-0.2 0.6,-0.2
  lines w0.2: -2.384,1.691 ccw(c-2.353,-0.005) -2.371,-1.7 ; -2.384,1.692 2.38,1.692 ; -2.353,-1.694 2.355,-1.694 ; -1.4,0.018 -1.229,0.018 ; -1.218,0.018 -1,-0.2 -0.6,0.2 -0.2,-0.2 0.2,0.2 0.6,-0.2 1,0.2 ; -0.75,-0.75 0.7,0.7 ; 0.3,0.7 0.7,0.7 ; 0.7,0.3 0.7,0.7 ; 1.049,0.2 1.232,0.018 1.4,0.018 ; 2.347,-1.694 ccw(c2.355,0.002) 2.38,1.698
3D body: height 4, standoff 1, extent 2.302,-0.299 2.9,0.3
3D body: height 4, standoff 1, extent -2.9,-0.3 -2.302,0.299
3D body: height 6.75, standoff 1.25, extent -2.752,-1.638 2.748,1.692
3D body: height 2, standoff -1, extent 2.327,-0.274 2.875,0.275
3D body: height 2, standoff -1, extent -2.874,-0.274 -2.326,0.274

## PS_HP03S1200WJ_SMPS_12VDC-3W [mm]
pads (5):
  rrect50% 2.5x3.5 hole 1.5: 1(-15.24,-8.75) 2(-10.16,-8.75) 3(15.24,-8.75) 4(15.24,8.75) 5(10.16,8.75)
Top Overlay:
  lines w0.254: -18.54,-12.05 18.46,-12.05 18.46,11.95 -18.54,11.95 -18.54,-12.05
  text "HP03S1200WJ" at -9.14,-0.75 h3
Bottom Overlay:
  lines w0.254: -18.54,-12.05 18.46,-12.05 18.46,11.95 -18.54,11.95 -18.54,-12.05
  text "L" at -14.24,-6.05 h3
  text "N" at -9.04,-6.05 h3
  text "V" at 11.36,4.15 h3
  text "G" at 16.31,4.1 h3
3D body: height 6, standoff -4, extent -10.656,-9.249 -9.66,-8.251
3D body: height 6, standoff -4, extent -15.736,-9.249 -14.74,-8.251
3D body: height 6, standoff -4, extent 14.744,-9.249 15.74,-8.251
3D body: height 6, standoff -4, extent 14.744,8.251 15.74,9.249
3D body: height 15.5, standoff 0, extent -18.54,-12.05 18.36,11.95
3D body: height 6, standoff -4, extent 9.664,8.251 10.66,9.249

## PS_ZP10S1200W_SMPS_12VDC-10W [mm]
pads (4):
  rrect50% 3.5x2.5 hole 1.5: 1(-24,-6) 2(-24,6) 3(24,-6) 4(24,-1)
Top Overlay:
  lines w0.254: -28.4,-17.9 27.6,-17.9 27.6,18.1 -28.4,18.1 -28.4,-17.9
  text "ZP10S1200W" at -15.4,-1.4 h5
Bottom Overlay:
  lines w0.254: -28.4,-17.9 27.6,-17.9 27.6,18.1 -28.4,18.1 -28.4,-17.9
  text "L" at -17.9,-6.7 h3
  text "N" at -18,5 h3
  text "+Ve" at 20.4,-7 h3
  text "-Ve" at 20.3,-1.7 h3
3D body: height 21, standoff -4, extent -24.496,5.501 -23.5,6.499
3D body: height 21, standoff -4, extent -24.496,-6.499 -23.5,-5.501
3D body: height 21, standoff -4, extent 23.504,-1.499 24.5,-0.501
3D body: height 21, standoff -4, extent 23.504,-6.499 24.5,-5.501
3D body: height 25, standoff 0, extent -28.4,-17.9 27.6,18.1

## Q_SOT-23-3_NPN_BC847 [mm] "SOT23, 3-Leads, Body 2.90x2.45mm, Pitch 0.95mm, IPC Medium Density"
height 1.15
pads (3):
  rect 0.75x1.25 smd: 1(-0.95,-1.2) 2(0.95,-1.2) 3(0,1.2)
Top Overlay:
  circle w0.25: c-1.9,-1.2 r0.125
  lines w0.2: -1.9,-1.8 -1.9,-2.3 1.9,-2.3 1.9,2.3 -1.9,2.3 -1.9,-0.6 ; -1.5,0 -1.5,0.7 -0.95,0.7 ; 0.95,0.7 1.5,0.7 1.5,0
Mechanical 13:
  lines w0.1: -1.5,-0.7 -1.5,0.7 1.5,0.7 1.5,-0.7 -1.5,-0.7
3D body "SOT95P245X115-3N.step": height 1.15, standoff 0, extent -1.5,-1.3 1.5,1.3

## R_0603_4_array [mm] "Chip Array, Concave, 8-Leads, Pitch 0.80mm,  Body 3.20x1.60mm,  IPC Medium Density"
height 0.7
pads (8):
  rect 1x0.5 smd: 1(-0.9,1.2)
  rrect50% 1x0.5 smd: 2(-0.9,0.4) 3(-0.9,-0.4) 4(-0.9,-1.2) 5(0.9,-1.2) 6(0.9,-0.4) 7(0.9,0.4) 8(0.9,1.2)
Top Overlay:
  circle w0.1: c-1.4,1.8 r0.05
  lines w0.2: -0.1,-0.9 0.1,-0.7 -0.1,-0.5 0.1,-0.3 -0.1,-0.1 0.1,0.1 -0.1,0.3 0.1,0.5 -0.1,0.7 0.1,0.9 ; -1.7,-2.1 -1.7,2.1 1.7,2.1 1.7,-2.1 -1.7,-2.1
Mechanical 13:
  lines w0.1: -0.9,-1.675 -0.9,-1.55 ccw(c-0.9,-1.2) -0.9,-0.85 -0.9,-0.75 ccw(c-0.9,-0.4) -0.9,-0.05 -0.9,0.05 ccw(c-0.9,0.4) -0.9,0.75 -0.9,0.85 ccw(c-0.9,1.2) -0.9,1.55 -0.9,1.675 0.9,1.675 0.9,1.55 ccw(c0.9,1.2) 0.9,0.85 0.9,0.75 ccw(c0.9,0.4) 0.9,0.05 0.9,-0.05 ccw(c0.9,-0.4) 0.9,-0.75 0.9,-0.85 ccw(c0.9,-1.2) 0.9,-1.55 0.9,-1.675 -0.9,-1.675
3D body "R_0603_4_array.step": height 0.7, standoff 0, extent -0.95,-1.675 0.95,1.675

## R_0805 [mm]
height 0.65
pads (2):
  rrect50% 1x1.8 smd: 1(-1.1,0) 2(1.1,0)
Top Overlay:
  lines w0.125: 0,-1 0,-0.6 0.2,-0.5 -0.2,-0.3 0.2,-0.1 -0.2,0.1 0.2,0.3 -0.2,0.5 0,0.625 0,1 ; -2,-1.3 2,-1.3 2,1.3 -2,1.3 -2,-1.3
Mechanical 13:
  lines w0.1: -1.1,-0.725 -1.1,0.725 1.1,0.725 1.1,-0.725 -1.1,-0.725
3D body "R_0805.step": height 0.65, standoff 0, extent -1.1,-0.725 1.1,0.725

## R_1206 [mm]
height 0.65
pads (2):
  rrect50% 1.2x2.2 smd: 1(-1.6,0) 2(1.6,0)
Top Overlay:
  lines w0.125: 0,-0.9 0,-0.5 0.3,-0.3 -0.3,-0.1 0.3,0.1 -0.3,0.3 0,0.5 0,0.9 ; -2.5,-1.4 2.5,-1.4 2.5,1.4 -2.5,1.4 -2.5,-1.4
Mechanical 13:
  lines w0.1: -1.65,-0.9 -1.65,0.9 1.65,0.9 1.65,-0.9 -1.65,-0.9
3D body "R_1206.step": height 0.65, standoff 0, extent -1.65,-0.9 1.65,0.9

## R_1812 [mm] "Chip Resistor, 2-Leads, Body 4.50x3.00mm, IPC Medium Density"
height 0.6
pads (2):
  rrect50% 1.4x3 smd: 1(-1.975,0) 2(1.975,0)
Top Overlay:
  lines w0.125: 0,-1.3 0,-0.9 0.3,-0.7 -0.3,-0.5 0.3,-0.3 -0.3,-0.1 0.3,0.1 -0.3,0.3 0.3,0.5 -0.3,0.7 0,0.9 0,1.3 ; -3,-1.8 3,-1.8 3,1.8 -3,1.8 -3,-1.8
Assembly Top:
  lines w0.1: -2.3,-1.55 -2.3,1.55 2.3,1.55 2.3,-1.55 -2.3,-1.55
3D body "RESC4530X06N.step": height 0.6, standoff 0, extent -2.3,-1.55 2.3,1.55

## R_2512 [mm] "Chip Resistor, 2-Leads, Body 6.35x3.10mm, IPC Medium Density"
height 0.65
pads (2):
  rrect50% 2x3.5 smd: 1(-2.95,0) 2(2.95,0)
Top Overlay:
  lines w0.125: 0,-1.5 0,-1.1 0.3,-0.9 -0.3,-0.7 0.3,-0.5 -0.3,-0.3 0.3,-0.1 -0.3,0.1 0.3,0.3 -0.3,0.5 0.3,0.7 -0.3,0.9 0,1.1 0,1.5 ; -4.3,-2.1 4.3,-2.1 4.3,2.1 -4.3,2.1 -4.3,-2.1
Mechanical 13:
  lines w0.1: -3.275,-1.625 3.275,-1.625 3.275,1.625 -3.275,1.625 -3.275,-1.625
3D body "R_2512.step": height 0.65, standoff 0, extent -3.275,-1.625 3.275,1.625

## R_Axial_P10 [mm] "Resistors 7mm Length"
pads (2):
  rrect50% 1.5x2.2 hole 0.85: 1(-5,0) 2(5,0)
Top Overlay:
  lines w0.2: -2.8,0 -1.7,0 -1.1,0.9 0,-0.6 1,0.9 1.7,0 2.8,0 ; -6.2,-1.017 ccw(c-5.717,-1.017) -5.717,-1.5 5.7,-1.5 ccw(c5.7,-1.017) 6.183,-1.017 6.183,1 ccw(c5.7,1) 5.7,1.483 -5.717,1.483 ccw(c-5.717,1) -6.2,1 -6.2,-1.017
3D body "User Library-Res40-Axial 0_25W-2_2R.step": height 2.41, standoff -2, extent -5.38,-1.2 5.38,1.2

## R_Axial_P13 [mm] "Resistors 10.5mm Length"
pads (2):
  rrect50% 1.5x2.2 hole 0.85: 1(-6.5,0) 2(6.5,0)
Top Overlay:
  lines w0.2: -6.725,2 6.725,2 ; -6.7,2 ccw(c-6.7,1) -7.7,1 -7.7,-1.1 ccw(c-6.7,-1.1) -6.7,-2.1 6.725,-2.1 ; -4.7,0 -2.7,0 -2.1,0.9 -1.1,-0.6 -0.1,0.9 1,-0.6 2,0.9 2.7,0 4.5,0 ; 6.7,-2.1 ccw(c6.7,-1.1) 7.7,-1.1 7.7,1 ccw(c6.7,1) 6.7,2
3D body "User Library-Res50-Axial 0_5W-2_2K.step": height 5.87, standoff -3.5, extent -6.725,-1.875 6.725,1.875

## R_Axial_P15 [mm] "Resistors 12mm Length"
pads (2):
  rrect50% 1.5x2.2 hole 0.9: 1(-7.5,0) 2(7.5,0)
Top Overlay:
  lines w0.2: -4.7,0 -2.7,0 -2.1,0.9 -1.1,-0.6 -0.1,0.9 1,-0.6 2,0.9 2.7,0 4.5,0 ; -8.7,-1.1 ccw(c-7.7,-1.1) -7.7,-2.1 7.7,-2.1 ccw(c7.7,-1.1) 8.7,-1.1 8.7,1 ccw(c7.7,1) 7.7,2 -7.7,2 ccw(c-7.7,1) -8.7,1 -8.7,-1.1
3D body "User Library-Res50-Axial 0_5W-2_2K.step": height 5.87, standoff -3.5, extent -6.725,-1.875 6.725,1.875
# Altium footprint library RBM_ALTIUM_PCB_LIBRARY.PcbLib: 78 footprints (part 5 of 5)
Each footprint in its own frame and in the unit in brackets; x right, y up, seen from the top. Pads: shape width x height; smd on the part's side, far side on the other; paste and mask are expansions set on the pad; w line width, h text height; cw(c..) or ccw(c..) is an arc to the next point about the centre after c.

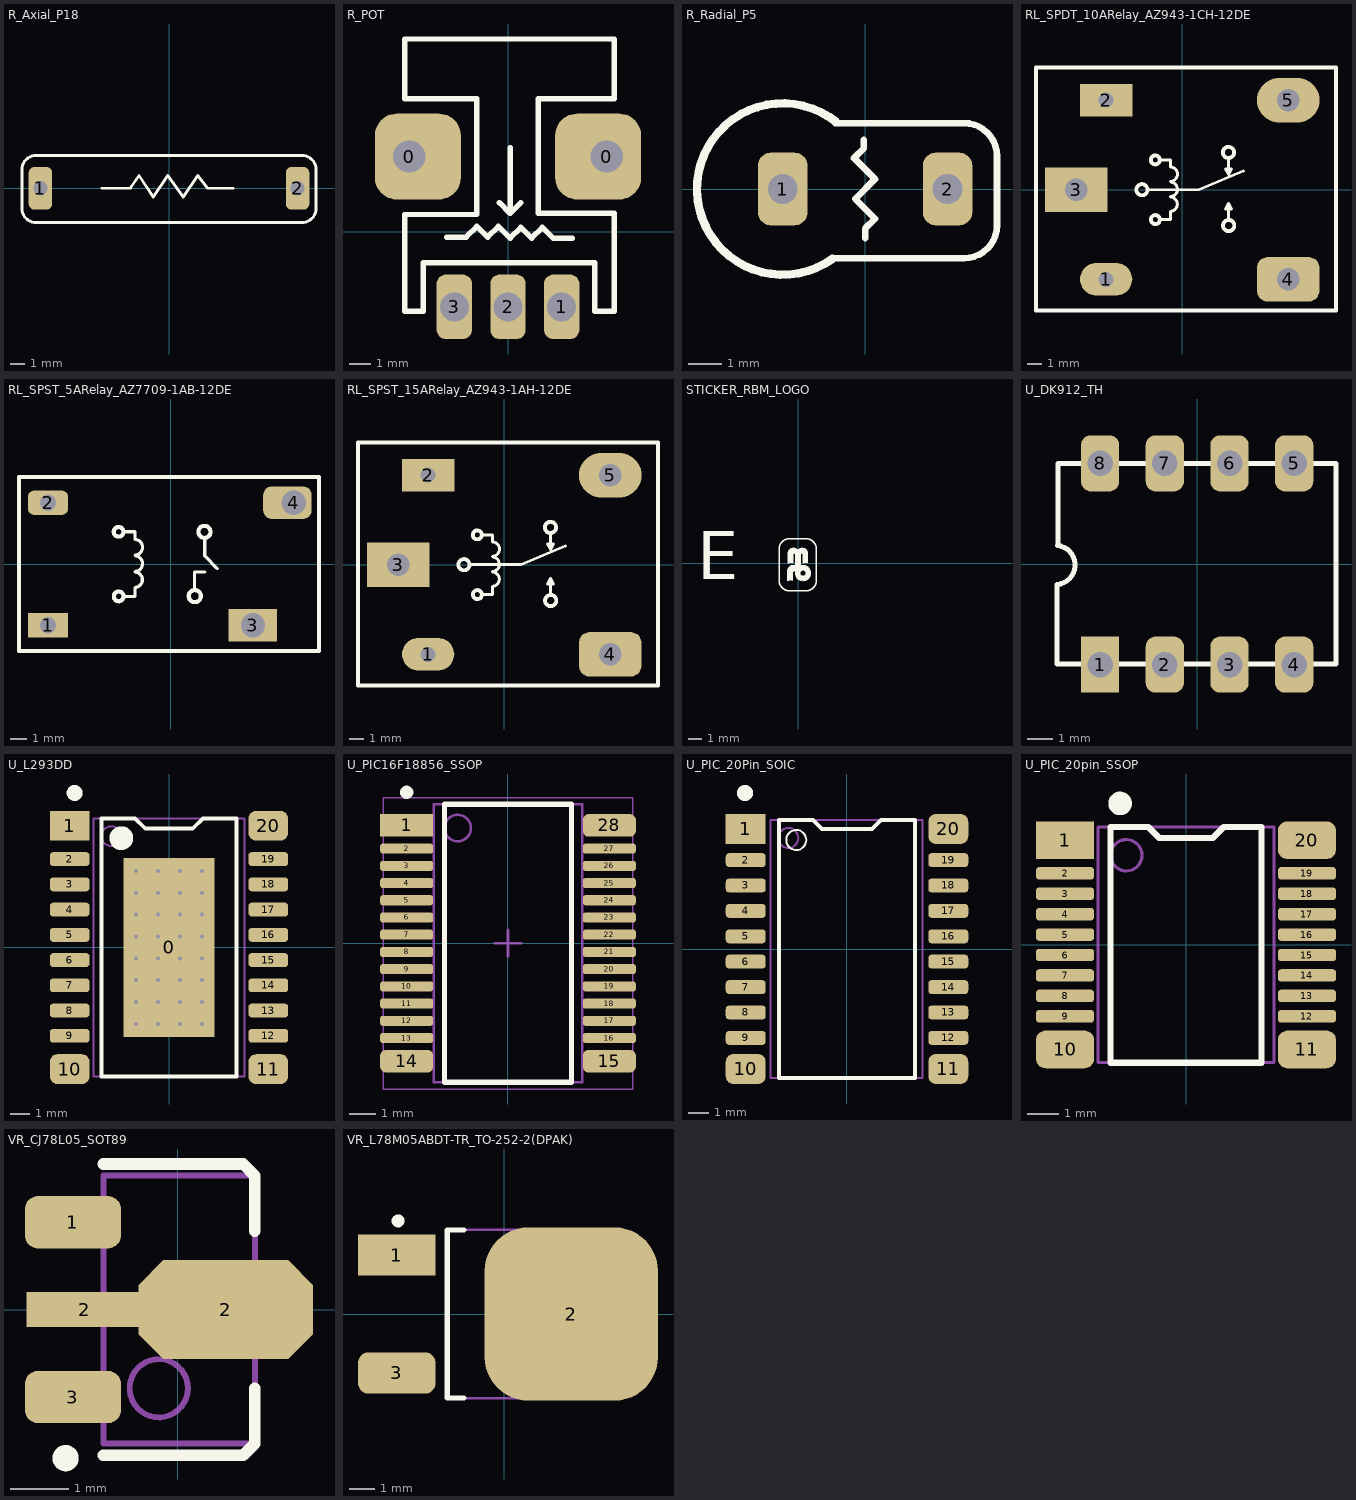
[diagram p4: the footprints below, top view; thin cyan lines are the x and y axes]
## R_Axial_P18 [mm] "220 ohm 2W 5%"
pads (2):
  rrect50% 1.65x3 hole 1: 1(-9,0) 2(9,0)
Top Overlay:
  lines w0.2: -4.7,0 -2.7,0 -2.1,0.9 -1.1,-0.6 -0.1,0.9 1,-0.6 2,0.9 2.7,0 4.5,0 ; -10.3,-1.4 ccw(c-9.3,-1.4) -9.3,-2.4 9.3,-2.4 ccw(c9.3,-1.4) 10.3,-1.4 10.3,1.3 ccw(c9.3,1.3) 9.3,2.3 -9.3,2.3 ccw(c-9.3,1.3) -10.3,1.3 -10.3,-1.4

## R_POT [mm]
pads (5):
  rrect50% 4x4 hole 1.5 square copper offset 0.4,0: 0(-4.6,3.5)
  rrect50% 4x4 hole 1.5 square copper offset -0.4,0: 0(4.6,3.5)
  rrect50% 1.65x3 hole 1.35: 1(2.5,-3.5) 2(0,-3.5) 3(-2.5,-3.5)
Top Overlay:
  lines w0.254: -2.85,-0.25 -1.95,-0.25 -1.45,0.25 ; -0.4,1.35 0.1,0.85 ; 0.05,-0.25 -0.45,0.25 ; 0.1,3.9 0.1,0.85 ; 0.6,1.35 0.1,0.85 ; 3,-0.3 2.1,-0.3 1.6,0.2 1.1,-0.3 ; -1.45,0.25 -0.95,-0.25 -0.45,0.25 ; -1.45,0.25 -1.45,0.25 ; -0.45,0.25 -0.45,0.25 ; 0.1,-0.3 0.6,0.2 1.1,-0.3 ; 0.1,-0.3 0.1,-0.3 ; 1.1,-0.3 1.1,-0.3 ; -4.8,-3.7 -3.95,-3.7 -3.95,-1.45 4.05,-1.45 4.05,-3.7 4.952,-3.7 4.952,0.85 1.4,0.85 1.4,6.2 4.952,6.2 4.952,8.975 -4.8,8.975 -4.8,6.2 -1.45,6.2 -1.45,0.8 -4.8,0.8 -4.8,-3.7
3D body "SW3dPS-Potentiometer 250U.STEP": height 15.26, standoff -3.8, extent -4.876,-3.8 4.876,8.75

## R_Radial_P5 [mm] "All Through Hole Resistors"
pads (2):
  rrect50% 1.5x2.2 hole 0.9: 1(-2.5,0) 2(2.5,0)
Top Overlay:
  lines w0.2: -1,-2.1 3,-2.1 ccw(c3,-1.1) 4,-1.1 4,1 ccw(c3,1) 3,2 -0.9,2 ; -0.038,1.5 -0.038,1.238 -0.337,0.938 0.3,0.3 ; 0,-1.5 0,-1.2 0.3,-0.9 -0.3,-0.3 ; -0.3,-0.3 -0.3,-0.3 ; -0.3,-0.3 0.3,0.3 ; 0.3,0.3 0.3,0.3
  lines w0.254: -0.989,-2.116 cw(c-2.5,0) -0.876,2.03
3D body "Res_Radial_5mmP.STEP": height 15.25, standoff -3, extent -5,-2.5 2.75,2.5

## RL_SPDT_10ARelay_AZ943-1CH-12DE [mm]
pads (5):
  oval 3.5x2.2 hole 1: 1(-5.1,-6)
  rect 3.5x2.2 hole 1: 2(-5.1,6)
  rect 4.2x3 hole 1.5: 3(-7.1,0)
  rrect50% 4.2x3 hole 1.5: 4(7.1,-6)
  oval 4.2x3 hole 1.5: 5(7.1,6)
Top Overlay:
  circle w0.254: c-2.704,0 r0.376
  circle w0.254: c3.096,2.5 r0.376
  circle w0.254: c3.111,-2.4 r0.376
  circle w0.254: c-1.804,2 r0.3
  circle w0.254: c-1.8,-2.001 r0.3
  lines w0.2: -2.329,0 1.096,0 4.109,1.268 ; -1.429,2 -0.789,2 -0.789,1.534 ; -1.424,-2.001 -0.784,-2.001 ; -0.791,-1.444 ccw(c-0.81,-0.968) -0.789,-0.492 ; -0.79,-0.458 ccw(c-0.81,0.028) -0.747,0.511 ; -0.79,0.559 ccw(c-0.81,1.046) -0.789,1.533 ; -0.789,-1.986 -0.789,-1.477 ; 3.096,-2.039 3.096,-0.906 ; 3.111,2.139 3.111,1.006 ; 2.896,1.4 3.111,1.4 ; 2.896,1.4 3.111,1.006 ; 2.896,1.4 3.111,1.006 ; 3.096,-1.3 2.896,-1.3 3.096,-0.906 ; 3.096,-1.3 3.096,-0.906 ; 3.096,-1.3 3.311,-1.3 ; 3.096,-0.906 3.311,-1.3 ; 3.096,-0.906 3.311,-1.3 ; 3.111,1.006 3.311,1.4 3.111,1.4 ; 3.111,1.006 3.111,1.4
  lines w0.254: -9.8,8.2 -9.8,-8.1 10.3,-8.1 10.3,8.2 -9.7,8.2
3D body: height 15, standoff 0.56, extent -9.8,-8.1 10.3,8.2
3D body: height 3, standoff -4, extent 6.505,-6.599 7.7,-5.401
3D body: height 3, standoff -4, extent 6.505,5.401 7.7,6.599
3D body: height 3, standoff -4, extent -5.348,5.751 -4.85,6.25
3D body: height 3, standoff -4, extent -7.695,-0.599 -6.5,0.599
3D body: height 3, standoff -4, extent -5.348,-6.249 -4.85,-5.75

## RL_SPST_5ARelay_AZ7709-1AB-12DE [mm]
pads (4):
  rect 2.5x1.5 hole 1: 1(-7.62,-3.8)
  rrect50% 2.5x1.5 hole 1: 2(-7.62,3.8)
  rect 3x2 hole 1.5: 3(5.08,-3.8)
  rrect50% 3x2 hole 1.5 copper offset -0.4,0: 4(7.62,3.8)
Top Overlay:
  circle w0.254: c2.08,1.993 r0.376
  circle w0.254: c1.48,-1.993 r0.376
  circle w0.254: c-3.24,-2.008 r0.3
  circle w0.254: c-3.244,1.993 r0.3
  lines w0.2: -2.869,1.993 -2.229,1.993 -2.229,1.526 ; -2.865,-2.008 -2.225,-2.008 ; -2.231,-1.451 ccw(c-2.25,-0.975) -2.229,-0.499 ; -2.231,-0.466 ccw(c-2.25,0.021) -2.187,0.504 ; -2.231,0.552 ccw(c-2.25,1.039) -2.229,1.525 ; -2.229,-1.993 -2.229,-1.484 ; 1.465,-1.632 1.465,-0.499 2.095,-0.499 ; 2.095,1.631 2.095,0.499 2.88,-0.286
  lines w0.254: -9.42,-5.4 -9.42,5.4 9.18,5.4 9.18,-5.4 -9.42,-5.4
3D body: height 3, standoff -4, extent -7.868,-4.049 -7.37,-3.55
3D body: height 3, standoff -4, extent 4.485,-4.399 5.68,-3.201
3D body: height 3, standoff -4, extent -7.868,3.551 -7.37,4.05
3D body: height 3, standoff -4, extent 7.025,3.201 8.22,4.399
3D body: height 15.5, standoff 0.56, extent -9.42,-5.4 9.18,5.4

## RL_SPST_15ARelay_AZ943-1AH-12DE [mm]
pads (5):
  oval 3.5x2.2 hole 1: 1(-5.1,-6)
  rect 3.5x2.2 hole 1: 2(-5.1,6)
  rect 4.2x3 hole 1.5: 3(-7.1,0)
  rrect50% 4.2x3 hole 1.5: 4(7.1,-6)
  oval 4.2x3 hole 1.5: 5(7.1,6)
Top Overlay:
  circle w0.254: c-2.704,0.001 r0.376
  circle w0.254: c3.096,2.501 r0.376
  circle w0.254: c3.111,-2.399 r0.376
  circle w0.254: c-1.804,2.001 r0.3
  circle w0.254: c-1.8,-2 r0.3
  lines w0.2: -2.329,0.001 1.096,0.001 4.109,1.269 ; -1.429,2.001 -0.789,2.001 -0.789,1.535 cw(c-0.81,1.047) -0.79,0.56 ; -1.424,-2 -0.784,-2 ; -0.791,-1.443 ccw(c-0.81,-0.967) -0.789,-0.491 ; -0.79,-0.457 ccw(c-0.81,0.029) -0.747,0.512 ; -0.789,-1.985 -0.789,-1.476 ; 3.096,-2.038 3.096,-0.905 ; 3.111,2.14 3.111,1.007 ; 2.896,1.401 3.111,1.401 ; 2.896,1.401 3.111,1.007 ; 2.896,1.401 3.111,1.007 ; 3.096,-1.299 2.896,-1.299 3.096,-0.905 ; 3.096,-1.299 3.096,-0.905 ; 3.096,-1.299 3.311,-1.299 ; 3.096,-0.905 3.311,-1.299 ; 3.096,-0.905 3.311,-1.299 ; 3.111,1.007 3.311,1.401 3.111,1.401 ; 3.111,1.007 3.111,1.401
  lines w0.254: -9.8,8.2 -9.8,-8.1 10.3,-8.1 10.3,8.2 -9.7,8.2
3D body: height 15, standoff 0.56, extent -9.8,-8.1 10.3,8.2
3D body: height 3, standoff -4, extent 6.505,-6.599 7.7,-5.401
3D body: height 3, standoff -4, extent 6.505,5.401 7.7,6.599
3D body: height 3, standoff -4, extent -5.348,5.751 -4.85,6.25
3D body: height 3, standoff -4, extent -7.695,-0.599 -6.5,0.599
3D body: height 3, standoff -4, extent -5.348,-6.249 -4.85,-5.75

## STICKER_RBM_LOGO [mm]
Top Layer:
  region: 10,1.7
  region: 10,1.7
  region: 10,1.7
  region: 10,1.7
  region: -3.6,-0.95
  region: -3.6,-0.95
  region: -3.6,-0.95
  region: -3.6,-0.95
Top Overlay:
  drawing of 3 lines, arcs and shapes, not listed
  text "E" at -7.396,-2.341 h6
Bottom Overlay:
  drawing of 26 lines, arcs and shapes, not listed

## U_DK912_TH [mm]
pads (8):
  rect 1.5x2.2 hole 1: 1(-3.81,-3.95)
  rrect50% 1.5x2.2 hole 1: 2(-1.27,-3.95) 3(1.27,-3.95) 4(3.81,-3.95) 5(3.81,3.95) 6(1.27,3.95) 7(-1.27,3.95) 8(-3.81,3.95)
Top Overlay:
  lines w0.2: -5.5,-0.8 -5.5,-3.92 5.45,-3.92 5.45,3.95 -5.47,3.95 -5.47,0.724 ; -5.471,0.724 cw(c-5.559,-0.038) -5.47,-0.8
3D body "SW3DPS-DIP 8 IC-DEFAULT.STEP": height 5.58, standoff -3, extent -5.47,-3.92 5.45,3.95

## U_L293DD [mm] "SOIC, 20-Leads, Body 12.80x7.50mm, Pitch 1.27mm, Thermal Pad 9.00x4.60mm, IPC Medium Density"
height 2.65
pads (21):
  rect 4.6x9 smd: 0(0,0)
  rect 2x1.5 smd mask+0.3: 1(-5,6.125)
  rrect50% 2x0.7 smd mask+0.3: 2(-5,4.445) 3(-5,3.175) 4(-5,1.905) 5(-5,0.635) 6(-5,-0.635) 7(-5,-1.905) 8(-5,-3.175) 9(-5,-4.445) 12(5,-4.445) 13(5,-3.175) 14(5,-1.905) 15(5,-0.635) 16(5,0.635) 17(5,1.905) 18(5,3.175) 19(5,4.445)
  rrect50% 2x1.5 smd mask+0.3: 10(-5,-6.125) 11(5,-6.125) 20(5,6.125)
via -1.65,3.85 diameter 0.5 hole 0.2
via -0.55,3.85 diameter 0.5 hole 0.2
via 0.55,3.85 diameter 0.5 hole 0.2
via 1.65,3.85 diameter 0.5 hole 0.2
via -1.65,2.75 diameter 0.5 hole 0.2
via -0.55,2.75 diameter 0.5 hole 0.2
via 0.55,2.75 diameter 0.5 hole 0.2
via 1.65,2.75 diameter 0.5 hole 0.2
via -1.65,1.65 diameter 0.5 hole 0.2
via -0.55,1.65 diameter 0.5 hole 0.2
via 0.55,1.65 diameter 0.5 hole 0.2
via 1.65,1.65 diameter 0.5 hole 0.2
via -1.65,0.55 diameter 0.5 hole 0.2
via -0.55,0.55 diameter 0.5 hole 0.2
via 0.55,0.55 diameter 0.5 hole 0.2
via 1.65,0.55 diameter 0.5 hole 0.2
via -1.65,-0.55 diameter 0.5 hole 0.2
via -0.55,-0.55 diameter 0.5 hole 0.2
via 0.55,-0.55 diameter 0.5 hole 0.2
via 1.65,-0.55 diameter 0.5 hole 0.2
via -1.65,-1.65 diameter 0.5 hole 0.2
via -0.55,-1.65 diameter 0.5 hole 0.2
via 0.55,-1.65 diameter 0.5 hole 0.2
via 1.65,-1.65 diameter 0.5 hole 0.2
via -1.65,-2.75 diameter 0.5 hole 0.2
via -0.55,-2.75 diameter 0.5 hole 0.2
via 0.55,-2.75 diameter 0.5 hole 0.2
via 1.65,-2.75 diameter 0.5 hole 0.2
via -1.65,-3.85 diameter 0.5 hole 0.2
via -0.55,-3.85 diameter 0.5 hole 0.2
via 0.55,-3.85 diameter 0.5 hole 0.2
via 1.65,-3.85 diameter 0.5 hole 0.2
Top Overlay:
  circle w0.6: c-2.4,5.5 r0.3
  circle w0.4: c-4.75,7.775 r0.2
  lines w0.2: -3.4,-6.5 -3.4,6.5 -1.7,6.5 -1.175,5.975 1.175,5.975 1.7,6.5 3.4,6.5 3.4,-6.5 -3.4,-6.5
Assembly Top:
  circle w0.1: c-2.9,5.6 r0.5
  lines w0.1: -3.8,-6.5 -3.8,6.5 3.8,6.5 3.8,-6.5 -3.8,-6.5
Courtyard Top:
  lines w0.1: -0.5,0 0.5,0 ; 0,-0.5 0,0.5
3D body "SOIC127P1030X265_HS-21N.step": height 2.65, standoff 0, extent -5.162,-6.5 5.162,6.5

## U_PIC16F18856_SSOP [mm] "SOP, 28-Leads, Body 10.20x5.30mm, Pitch 0.65mm, Thermal Pad 8.00x4.00mm, IPC Medium Density"
height 2
pads (28):
  rect 2x0.85 smd mask+0.2: 1(-3.825,4.45)
  rrect50% 2x0.38 smd mask+0.2: 2(-3.825,3.575) 3(-3.825,2.925) 4(-3.825,2.275) 5(-3.825,1.625) 6(-3.825,0.975) 7(-3.825,0.325) 8(-3.825,-0.325) 9(-3.825,-0.975) 10(-3.825,-1.625) 11(-3.825,-2.275) 12(-3.825,-2.925) 13(-3.825,-3.575) 16(3.825,-3.575) 17(3.825,-2.925) 18(3.825,-2.275) 19(3.825,-1.625) 20(3.825,-0.975) 21(3.825,-0.325) 22(3.825,0.325) 23(3.825,0.975) 24(3.825,1.625) 25(3.825,2.275) 26(3.825,2.925) 27(3.825,3.575)
  rrect50% 2x0.85 smd mask+0.2: 14(-3.825,-4.45) 15(3.825,-4.45) 28(3.825,4.45)
Top Overlay:
  circle w0.25: c-3.825,5.7 r0.125
  lines w0.2: -2.4,-5.25 2.4,-5.25 2.4,5.25 -2.4,5.25 -2.4,-5.25
Assembly Top:
  circle w0.1: c-1.9,4.35 r0.5
  lines w0.1: -2.8,-5.25 2.8,-5.25 2.8,5.25 -2.8,5.25 -2.8,-5.25
Courtyard Top:
  lines w0.05: -4.7,-5.5 4.7,-5.5 4.7,5.5 -4.7,5.5 -4.7,-5.5
  lines w0.1: -0.5,0 0.5,0 ; 0,-0.5 0,0.5
3D body "U_PIC16F18856_SSOP.step": height 2, standoff 0, extent -3.9,-5.25 3.9,5.25

## U_PIC_20Pin_SOIC [mm] "SOIC, 20-Leads, Body 12.80x7.50mm, Pitch 1.27mm, IPC Medium Density"
height 2.65
pads (20):
  rect 2x1.5 smd mask+0.3: 1(-5.063,6)
  rrect50% 2x0.7 smd mask+0.3: 2(-5.063,4.445) 3(-5.063,3.175) 4(-5.063,1.905) 5(-5.063,0.635) 6(-5.063,-0.635) 7(-5.063,-1.905) 8(-5.063,-3.175) 9(-5.063,-4.445) 12(5.063,-4.445) 13(5.063,-3.175) 14(5.063,-1.905) 15(5.063,-0.635) 16(5.063,0.635) 17(5.063,1.905) 18(5.063,3.175) 19(5.063,4.445)
  rrect50% 2x1.5 smd mask+0.3: 10(-5.063,-6) 11(5.063,-6)
  rrect50% 2x1.5 smd paste+0 mask+0.3: 20(5.063,6)
Top Overlay:
  circle w0.1: c-2.537,5.45 r0.5
  circle w0.4: c-5.1,7.8 r0.2
  lines w0.2: -3.4,-6.45 3.4,-6.45 3.4,6.45 1.7,6.45 1.25,6 -1.25,6 -1.7,6.45 -3.4,6.45 -3.4,-6.45
Mechanical 13:
  circle w0.1: c-2.937,5.55 r0.5
  lines w0.1: -3.837,-6.45 3.763,-6.45 3.763,6.45 -3.837,6.45 -3.837,-6.45
3D body "SOIC127P1020X265-20N.step": height 2.65, standoff 0, extent -5.062,-6.425 5.088,6.475

## U_PIC_20pin_SSOP [mm] "SOP, 20-Leads, Body 7.20x5.30mm, Pitch 0.65mm, IPC Medium Density"
height 2
pads (20):
  rect 1.85x1.2 smd mask+0.2: 1(-3.85,3.33)
  rrect50% 1.85x0.395 smd mask+0.2: 2(-3.85,2.275) 3(-3.85,1.625) 4(-3.85,0.975) 5(-3.85,0.325) 6(-3.85,-0.325) 7(-3.85,-0.975) 8(-3.85,-1.625) 9(-3.85,-2.275) 12(3.85,-2.275) 13(3.85,-1.625) 14(3.85,-0.975) 15(3.85,-0.325) 16(3.85,0.325) 17(3.85,0.975) 18(3.85,1.625) 19(3.85,2.275)
  rrect50% 1.85x1.2 smd mask+0.2: 10(-3.85,-3.33) 11(3.85,-3.33) 20(3.85,3.33)
Top Overlay:
  circle w0.5: c-2.1,4.5 r0.125
  lines w0.2: -2.4,-3.75 2.4,-3.75 2.4,3.75 1.2,3.75 0.85,3.4 -0.85,3.4 -1.2,3.75 -2.4,3.75 -2.4,-3.75
Mechanical 13:
  circle w0.1: c-1.9,2.85 r0.5
  lines w0.1: -2.8,-3.75 2.8,-3.75 2.8,3.75 -2.8,3.75 -2.8,-3.75
3D body "SOP65P780X200-20N.step": height 2, standoff 0, extent -3.9,-3.75 3.9,3.75

## VR_CJ78L05_SOT89 [mm] "SOT89, 3-Leads, Body 4.50x2.45mm, Pitch 1.50mm, Lead Span 4.1mm - Reverse Pinning, IPC Medium Density"
height 1.6
pads (4):
  rrect50% 1.65x0.9 smd: 1(-1.8,1.5) 3(-1.8,-1.5)
  rect 2x0.6 smd: 2(-1.6,0)
  oct 3x1.7 smd: 2(0.823,0)
Top Overlay:
  circle w0.25: c-1.927,-2.55 r0.1
  lines w0.2: -1.278,-2.5 1.122,-2.5 1.322,-2.3 1.322,-1.35 ; -1.278,2.5 1.122,2.5 1.322,2.3 1.322,1.35
Mechanical 13:
  circle w0.1: c-0.327,-1.35 r0.5
  lines w0.1: -1.278,-2.3 1.322,-2.3 1.322,2.3 -1.278,2.3 -1.278,-2.3
3D body "SOT89R-150P410X160-3N.step": height 1.6, standoff 0, extent -2.2,-2.3 1.8,2.3

## VR_L78M05ABDT-TR_TO-252-2(DPAK) [mm] "D-PAK, 3-Pads, Body 6.20x6.61mm (max), IPC Medium Density"
height 2.4
pads (3):
  rect 3x1.6 smd: 1(-4.15,2.28)
  rrect50% 6.7x6.7 smd: 2(2.6,0)
  rrect50% 3x1.6 smd: 3(-4.15,-2.28)
Top Overlay:
  circle w0.25: c-4.1,3.6 r0.125
  lines w0.2: -1.55,-3.25 -2.2,-3.25 -2.2,3.25 -1.55,3.25
Mechanical 13:
  lines w0.1: -2.2,-3.25 4,-3.25 4,3.25 -2.2,3.25 -2.2,-3.25
3D body "ST7805.step": height 2.5, standoff 0, extent -4.275,-3.25 5.45,3.25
